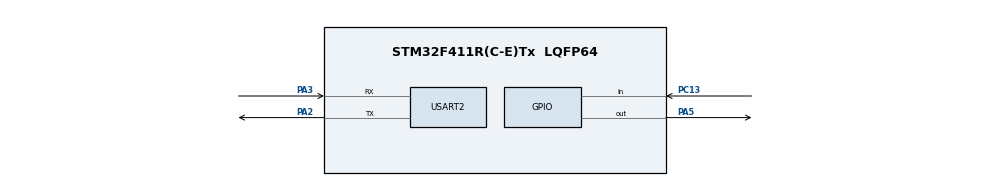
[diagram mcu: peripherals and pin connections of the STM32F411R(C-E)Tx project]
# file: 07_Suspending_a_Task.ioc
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FREERTOS.Tasks01=defaultTask,24,128,StartDefaultTask,Default,NULL,Dynamic,NULL,NULL
Mcu.Family=STM32F4
Mcu.Name=STM32F411R(C-E)Tx
Mcu.Package=LQFP64
NVIC.PriorityGroup=NVIC_PRIORITYGROUP_4
NVIC.TIM1_UP_TIM10_IRQn=true\:15\:0\:false\:false\:true\:false\:false\:true\:true
NVIC.TimeBase=TIM1_UP_TIM10_IRQn
NVIC.TimeBaseIP=TIM1
PA13.Signal=SYS_JTMS-SWDIO
PA14.Signal=SYS_JTCK-SWCLK
PA2.GPIO_Speed=GPIO_SPEED_FREQ_VERY_HIGH
PA2.Mode=Asynchronous
PA2.Signal=USART2_TX
PA3.Mode=Asynchronous
PA3.Signal=USART2_RX
PA5.Signal=GPIO_Output
PC13-ANTI_TAMP.Signal=GPIO_Input
PC14-OSC32_IN.Mode=LSE-External-Oscillator
PC14-OSC32_IN.Signal=RCC_OSC32_IN
PC15-OSC32_OUT.Mode=LSE-External-Oscillator
PC15-OSC32_OUT.Signal=RCC_OSC32_OUT
PH0\ -\ OSC_IN.Mode=HSE-External-Clock-Source
PH0\ -\ OSC_IN.Signal=RCC_OSC_IN
PH1\ -\ OSC_OUT.Mode=HSE-External-Clock-Source
PH1\ -\ OSC_OUT.Signal=RCC_OSC_OUT
ProjectManager.HeapSize=0x200
ProjectManager.StackSize=0x400
ProjectManager.TargetToolchain=STM32CubeIDE
RCC.48MHZClocksFreq_Value=50000000
RCC.AHBFreq_Value=100000000
RCC.APB1CLKDivider=RCC_HCLK_DIV2
RCC.APB1Freq_Value=50000000
RCC.APB1TimFreq_Value=100000000
RCC.APB2Freq_Value=100000000
RCC.APB2TimFreq_Value=100000000
RCC.CortexFreq_Value=100000000
RCC.HCLKFreq_Value=100000000
RCC.HSE_VALUE=8000000
RCC.HSI_VALUE=16000000
RCC.PLLM=8
RCC.PLLN=100
RCC.SYSCLKFreq_VALUE=100000000
RCC.SYSCLKSource=RCC_SYSCLKSOURCE_PLLCLK
RCC.VCOOutputFreq_Value=200000000
USART2.VirtualMode=VM_ASYNC
VP_FREERTOS_VS_CMSIS_V2.Mode=CMSIS_V2
VP_SYS_VS_tim1.Mode=TIM1
board=custom

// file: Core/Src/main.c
#include "main.h"
#include "cmsis_os.h"
#include <stdio.h>

UART_HandleTypeDef huart2;

void SystemClock_Config(void);
static void MX_GPIO_Init(void);
static void MX_USART2_UART_Init(void);

/* Redirect putchar to serial UART*/
int __io_putchar(int ch);
/* task 1 prototype*/
void vBlueLedControllerTask(void *pParameters);
/* task 2 prototype*/
void vRedLedControllerTask(void *pParameters);
/* task 3 prototype*/
void vGreenLedControllerTask(void *pParameters);

/* Counters for tasks */
typedef uint32_t TaskProfiler;
TaskProfiler blueTaskProfiler, redTaskProfiler, greenTaskProfiler;
TaskHandle_t blue_handle, red_handle, green_handle;
uint32_t green_priority;

int msg[1] = {'H'};

int main(void)
{
  HAL_Init();
  SystemClock_Config();
  MX_GPIO_Init();
  MX_USART2_UART_Init();
  xTaskCreate(vBlueLedControllerTask,"Blue Led Controller", 100, NULL,1, &blue_handle);
  xTaskCreate(vRedLedControllerTask,"Red Led Controller", 100, NULL,1, &red_handle);
  xTaskCreate(vGreenLedControllerTask,"Green Led Controller", 100, NULL,1, &green_handle);

  vTaskStartScheduler();

  while (1)
  {

  }
}

/* Function linked to task 1 (vBlueLedControllerTask)*/
void vBlueLedControllerTask(void *pParameters)
{
  int i;
  while(1)
  {
    blueTaskProfiler ++;
    for(i=0;i<100000;i++){}
  }
}

/* Suspend monitor */
uint32_t suspend_monitor;

/* Function linked to task 2 (vRedLedControllerTask)*/
void vRedLedControllerTask(void *pParameters)
{
  int i;
  while(1)
  {
    redTaskProfiler++;
    for(i=0;i<100000;i++){}
    suspend_monitor++;
    if(suspend_monitor >= 50)
    {
      /*blue task is suspended when suspend_monitor is greater than or equal to 50*/
      vTaskSuspend(blue_handle);
    }
  }
}

/* Function linked to task 3 (vGreenLedControllerTask)*/
void vGreenLedControllerTask(void *pParameters)
{
  int i;
  while(1)
  {
    greenTaskProfiler++;
    for(i=0;i<100000;i++){}
  }
}

/* Redirect putchar to serial UART*/
int __io_putchar(int ch)
{
  HAL_UART_Transmit(&huart2,(uint8_t *)&ch, 1,0xFFFF);
  return ch;
}

void SystemClock_Config(void)
{
  RCC_OscInitTypeDef RCC_OscInitStruct = {0};
  RCC_ClkInitTypeDef RCC_ClkInitStruct = {0};

  /** Configure the main internal regulator output voltage
  */
  __HAL_RCC_PWR_CLK_ENABLE();
  __HAL_PWR_VOLTAGESCALING_CONFIG(PWR_REGULATOR_VOLTAGE_SCALE1);

  /** Initializes the RCC Oscillators according to the specified parameters
  * in the RCC_OscInitTypeDef structure.
  */
  RCC_OscInitStruct.OscillatorType = RCC_OSCILLATORTYPE_HSI;
  RCC_OscInitStruct.HSIState = RCC_HSI_ON;
  RCC_OscInitStruct.HSICalibrationValue = RCC_HSICALIBRATION_DEFAULT;
  RCC_OscInitStruct.PLL.PLLState = RCC_PLL_ON;
  RCC_OscInitStruct.PLL.PLLSource = RCC_PLLSOURCE_HSI;
  RCC_OscInitStruct.PLL.PLLM = 16;
  RCC_OscInitStruct.PLL.PLLN = 336;
  RCC_OscInitStruct.PLL.PLLP = RCC_PLLP_DIV4;
  RCC_OscInitStruct.PLL.PLLQ = 4;
  if (HAL_RCC_OscConfig(&RCC_OscInitStruct) != HAL_OK)
  {
    Error_Handler();
  }

  /** Initializes the CPU, AHB and APB buses clocks
  */
  RCC_ClkInitStruct.ClockType = RCC_CLOCKTYPE_HCLK|RCC_CLOCKTYPE_SYSCLK
                              |RCC_CLOCKTYPE_PCLK1|RCC_CLOCKTYPE_PCLK2;
  RCC_ClkInitStruct.SYSCLKSource = RCC_SYSCLKSOURCE_PLLCLK;
  RCC_ClkInitStruct.AHBCLKDivider = RCC_SYSCLK_DIV1;
  RCC_ClkInitStruct.APB1CLKDivider = RCC_HCLK_DIV2;
  RCC_ClkInitStruct.APB2CLKDivider = RCC_HCLK_DIV1;

  if (HAL_RCC_ClockConfig(&RCC_ClkInitStruct, FLASH_LATENCY_2) != HAL_OK)
  {
    Error_Handler();
  }
}

static void MX_USART2_UART_Init(void)
{

  huart2.Instance = USART2;
  huart2.Init.BaudRate = 115200;
  huart2.Init.WordLength = UART_WORDLENGTH_8B;
  huart2.Init.StopBits = UART_STOPBITS_1;
  huart2.Init.Parity = UART_PARITY_NONE;
  huart2.Init.Mode = UART_MODE_TX_RX;
  huart2.Init.HwFlowCtl = UART_HWCONTROL_NONE;
  huart2.Init.OverSampling = UART_OVERSAMPLING_16;
  if (HAL_UART_Init(&huart2) != HAL_OK)
  {
    Error_Handler();
  }

}

static void MX_GPIO_Init(void)
{
  GPIO_InitTypeDef GPIO_InitStruct = {0};

  /* GPIO Ports Clock Enable */
  __HAL_RCC_GPIOC_CLK_ENABLE();
  __HAL_RCC_GPIOH_CLK_ENABLE();
  __HAL_RCC_GPIOA_CLK_ENABLE();
  __HAL_RCC_GPIOB_CLK_ENABLE();

  /*Configure GPIO pin Output Level */
  HAL_GPIO_WritePin(LD2_GPIO_Port, LD2_Pin, GPIO_PIN_RESET);

  /*Configure GPIO pin : B1_Pin */
  GPIO_InitStruct.Pin = B1_Pin;
  GPIO_InitStruct.Mode = GPIO_MODE_IT_FALLING;
  GPIO_InitStruct.Pull = GPIO_NOPULL;
  HAL_GPIO_Init(B1_GPIO_Port, &GPIO_InitStruct);

  /*Configure GPIO pin : LD2_Pin */
  GPIO_InitStruct.Pin = LD2_Pin;
  GPIO_InitStruct.Mode = GPIO_MODE_OUTPUT_PP;
  GPIO_InitStruct.Pull = GPIO_NOPULL;
  GPIO_InitStruct.Speed = GPIO_SPEED_FREQ_LOW;
  HAL_GPIO_Init(LD2_GPIO_Port, &GPIO_InitStruct);

}

void HAL_TIM_PeriodElapsedCallback(TIM_HandleTypeDef *htim)
{
  if (htim->Instance == TIM1)
  {
    HAL_IncTick();
  }
}

void Error_Handler(void)
{
  __disable_irq();
  while (1)
  {
  }
}
